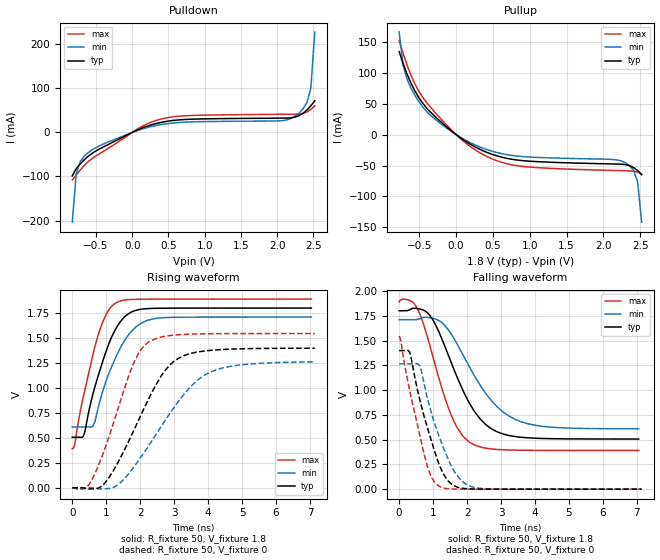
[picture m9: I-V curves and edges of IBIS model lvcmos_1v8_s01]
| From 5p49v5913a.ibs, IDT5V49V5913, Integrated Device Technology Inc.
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[Model]   lvcmos_1v8_s01
Model_type   Output
Polarity   Non-Inverting
|   typ   min   max
C_comp   2pF   1.5pF   2.5pF
Vmeas = 0.9V
Rref = 50
Cref = 0
Vref = 0.9V
|   typ   min   max
[Voltage range]   1.8V   1.71V   1.89V
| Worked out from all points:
|   slope of the pulldown table from 0 to 0.27 V, typ, clamps not added: 15.4 ohm
|   slope of the pullup table from 0 to 0.27 V, typ, clamps not added: 13.1 ohm
|   rising waveform, R_fixture 50, V_fixture 1.8: 20-80 % time 717ps typ, 785ps min, 628ps max; typ from 0.506 V to 1.8 V
|   falling waveform, R_fixture 50, V_fixture 1.8: 20-80 % time 1.03ns typ, 1.23ns min, 819ps max; typ from 1.8 V to 0.506 V
|   rising waveform, R_fixture 50, V_fixture 0: 20-80 % time 1.23ns typ, 1.57ns min, 924ps max; typ from 0 V to 1.4 V
|   falling waveform, R_fixture 50, V_fixture 0: 20-80 % time 678ps typ, 740ps min, 598ps max; typ from 1.4 V to 0 V
[Pulldown]
|Voltage   I (typ)   I (min)   I (max)
|Note, modeling breaks down at 250mA and above.  This is well beyond the functional   |
|operating range of the device.  Should this scenario occur, catastrophic failure and   |
|possible damage to the device and/or board is of higher concern than the I-V curve   |
|behavior.  The IBIS checker will flag currents in excess of 10A with warnings.  Lines   |
|with currents in excess of 0.35 A have been commented out.  The points still remain|
|available to the user if the user desires to use them.   |
|-1.80000e+00   -1.57123e+02   -1.41687e+02   -1.84032e+02
|-1.74600e+00   -1.46350e+02   -1.32525e+02   -1.70600e+02
|-1.69200e+00   -1.35593e+02   -1.23381e+02   -1.57181e+02
|-1.63800e+00   -1.24855e+02   -1.14259e+02   -1.43777e+02
|-1.58400e+00   -1.14140e+02   -1.05164e+02   -1.30391e+02
|-1.53000e+00   -1.03454e+02   -9.61014e+01   -1.17030e+02
|-1.47600e+00   -9.28051e+01   -8.70803e+01   -1.03700e+02
|-1.42200e+00   -8.22059e+01   -7.81126e+01   -9.04125e+01
|-1.36800e+00   -7.16734e+01   -6.92147e+01   -7.71843e+01
|-1.31400e+00   -6.12369e+01   -6.04138e+01   -6.40446e+01
|-1.26000e+00   -5.09378e+01   -5.17410e+01   -5.10499e+01
|-1.20600e+00   -4.08235e+01   -4.32303e+01   -3.82636e+01
|-1.15200e+00   -3.09387e+01   -3.49134e+01   -2.57664e+01
|-1.09800e+00   -2.12858e+01   -2.67907e+01   -1.35591e+01
|-1.04400e+00   -1.18008e+01   -1.88242e+01   -2.48786e+00
|-9.90000e-01   -2.94592e+00   -1.09564e+01   -3.30913e-01
|-9.36000e-01   -5.04093e-01   -3.41190e+00   -1.45436e-01
|-8.82000e-01   -1.55884e-01   -7.28672e-01   -1.19691e-01
-828mV    -98.74mA   -203.8mA   -107.8mA
-774mV    -82.54mA   -94.98mA   -96.94mA
-720mV    -71.89mA   -66.58mA   -85.84mA
-612mV    -54.71mA   -46.44mA   -66.79mA
-450mV    -37.4mA    -30.21mA   -48.14mA
144mV     10.52mA    8.041mA    14.45mA
468mV     24.92mA    19.47mA    32.9mA
2.034V    32.4mA     26.18mA    41.13mA
2.304V    38.17mA    44.17mA    41.74mA
2.412V    50.97mA    67.63mA    46.33mA
2.466V    60.46mA    100.4mA    52.18mA
2.52V     72.02mA    227.8mA    60.53mA
| 2.57400e+00   8.57382e-02   8.78094e-01   7.13755e-02
| 2.62800e+00   1.08415e-01   4.40618e+00   8.43612e-02
| 2.68200e+00   2.11755e-01   1.54961e+01   9.74736e-02
| 2.73600e+00   9.45213e-01   2.77829e+01   1.08890e-01
| 2.79000e+00   6.44762e+00   4.00829e+01   1.24073e-01
| 2.84400e+00   2.08796e+01   5.24028e+01   1.97645e-01
| 2.89800e+00   3.56490e+01   6.47465e+01   1.06236e+00
| 2.95200e+00   5.04441e+01   7.71133e+01   1.09978e+01
| 3.00600e+00   6.52701e+01   8.94994e+01   2.98762e+01
| 3.06000e+00   8.01244e+01   1.01900e+02   4.87902e+01
| 3.11400e+00   9.50001e+01   1.14313e+02   6.77471e+01
| 3.16800e+00   1.09892e+02   1.26734e+02   8.67385e+01
| 3.22200e+00   1.24795e+02   1.39162e+02   1.05753e+02
| 3.27600e+00   1.39706e+02   1.51595e+02   1.24783e+02
| 3.33000e+00   1.54624e+02   1.64032e+02   1.43824e+02
| 3.38400e+00   1.69547e+02   1.76473e+02   1.62872e+02
| 3.43800e+00   1.84473e+02   1.88917e+02   1.81926e+02
| 3.49200e+00   1.99403e+02   2.01364e+02   2.00984e+02
| 3.54600e+00   2.14336e+02   2.13813e+02   2.20045e+02
| 3.60000e+00   2.29271e+02   2.26263e+02   2.39110e+02
[Pullup]
|Voltage   I (typ)   I (min)   I (max)
|Note, modeling breaks down at 250mA and above.  This is well beyond the functional   |
|operating range of the device.  Should this scenario occur, catastrophic failure and   |
|possible damage to the device and/or board is of higher concern than the I-V curve   |
|behavior.  The IBIS checker will flag currents in excess of 10A with warnings.  Lines   |
|with currents in excess of 0.35 A have been commented out.  The points still remain|
|available to the user if the user desires to use them.   |
|-1.80000e+00   2.29375e+02   2.05604e+02   2.71011e+02
|-1.74600e+00   2.14438e+02   1.93155e+02   2.51941e+02
|-1.69200e+00   1.99503e+02   1.80708e+02   2.32873e+02
|-1.63800e+00   1.84571e+02   1.68264e+02   2.13807e+02
|-1.58400e+00   1.69642e+02   1.55823e+02   1.94744e+02
|-1.53000e+00   1.54718e+02   1.43387e+02   1.75685e+02
|-1.47600e+00   1.39798e+02   1.30955e+02   1.56630e+02
|-1.42200e+00   1.24884e+02   1.18529e+02   1.37582e+02
|-1.36800e+00   1.09978e+02   1.06112e+02   1.18541e+02
|-1.31400e+00   9.50841e+01   9.37042e+01   9.95128e+01
|-1.26000e+00   8.02054e+01   8.13103e+01   8.05016e+01
|-1.20600e+00   6.53483e+01   6.89341e+01   6.15174e+01
|-1.15200e+00   5.05195e+01   5.65798e+01   4.25710e+01
|-1.09800e+00   3.57213e+01   4.42495e+01   2.36670e+01
|-1.04400e+00   2.09487e+01   3.19407e+01   5.48601e+00
|-9.90000e-01   6.51330e+00   1.96473e+01   6.02004e-01
|-9.36000e-01   1.00727e+00   7.47441e+00   2.29344e-01
|-8.82000e-01   2.69913e-01   1.53012e+00   1.87713e-01
|-8.28000e-01   1.62186e-01   3.86408e-01   1.69987e-01
-774mV    134.2mA    165.8mA    151.8mA
-720mV    114.6mA    111.9mA    131.2mA
-666mV    97.64mA    89.72mA    112.2mA
-504mV    59.35mA    52.84mA    69.59mA
-342mV    35.66mA    30.61mA    43.41mA
-18mV     1.676mA    1.404mA    2.092mA
360mV     -25.81mA   -21.74mA   -31.86mA
900mV     -42.04mA   -35.5mA    -51.35mA
2.304V    -48.62mA   -45.83mA   -58.53mA
2.412V    -53.4mA    -58.27mA   -59.21mA
2.466V    -58.21mA   -76.35mA   -60.65mA
2.52V     -64.73mA   -141.7mA   -64.05mA
| 2.57400e+00   -7.32856e-02   -4.47707e-01   -6.97922e-02
| 2.62800e+00   -8.79644e-02   -2.00025e+00   -7.77007e-02
| 2.68200e+00   -1.43736e-01   -8.33672e+00   -8.69778e-02
| 2.73600e+00   -4.90693e-01   -1.61824e+01   -9.65121e-02
| 2.79000e+00   -2.93152e+00   -2.41086e+01   -1.08871e-01
| 2.84400e+00   -1.17857e+01   -3.21721e+01   -1.52056e-01
| 2.89800e+00   -2.12700e+01   -4.04227e+01   -5.63058e-01
| 2.95200e+00   -3.09224e+01   -4.88696e+01   -5.50618e+00
| 3.00600e+00   -4.08067e+01   -5.74918e+01   -1.75817e+01
| 3.06000e+00   -5.09214e+01   -6.62527e+01   -2.98766e+01
| 3.11400e+00   -6.12182e+01   -7.51218e+01   -4.24771e+01
| 3.16800e+00   -7.16546e+01   -8.40680e+01   -5.53423e+01
| 3.22200e+00   -8.21870e+01   -9.30724e+01   -6.83916e+01
| 3.27600e+00   -9.27859e+01   -1.02122e+02   -8.15645e+01
| 3.33000e+00   -1.03434e+02   -1.11207e+02   -9.48151e+01
| 3.38400e+00   -1.14120e+02   -1.20320e+02   -1.08118e+02
| 3.43800e+00   -1.24835e+02   -1.29457e+02   -1.21460e+02
| 3.49200e+00   -1.35573e+02   -1.38613e+02   -1.34829e+02
| 3.54600e+00   -1.46330e+02   -1.47785e+02   -1.48221e+02
| 3.60000e+00   -1.57103e+02   -1.56971e+02   -1.61631e+02
[Ramp]
|   typ   min   max
dV/dt_r   0.846/1.241n   0.763/1.578n   0.935/0.933n
dV/dt_f   0.791/1.045n   0.674/1.245n   0.916/0.832n
R_load =   50
[Rising Waveform]
R_fixture = 50
V_fixture = 1.8   |Vcc_typ
V_fixture_min = 1.71 |Vcc_min
V_fixture_max = 1.89 |Vcc_max
C_fixture = 0.0p
| Time   typ   min   max
| 0.00000e+00   5.05771e-01   6.08763e-01   3.90768e-01
| 2.47507e-12   5.05771e-01   6.08763e-01   3.90768e-01
| 4.34525e-12   5.05771e-01   6.08763e-01   3.90768e-01
| 4.57959e-12   5.05771e-01   6.08763e-01   3.90768e-01
| 7.76228e-12   5.05771e-01   6.08763e-01   3.90768e-01
| 1.40250e-11   5.05771e-01   6.08763e-01   3.90768e-01
| 1.46859e-11   5.05771e-01   6.08763e-01   3.90768e-01
| 2.75535e-11   5.05771e-01   6.08763e-01   3.90768e-01
| 3.89156e-11   5.05771e-01   6.08763e-01   3.90768e-01
| 4.27651e-11   5.05771e-01   6.08763e-01   3.90768e-01
| 5.19470e-11   5.05771e-01   6.08763e-01   3.90768e-01
| 6.09735e-11   5.05771e-01   6.08763e-01   3.90768e-01
| 6.28654e-11   5.05771e-01   6.08763e-01   3.90768e-01
| 7.18355e-11   5.05771e-01   6.08763e-01   3.90768e-01
| 7.20853e-11   5.05771e-01   6.08763e-01   3.90768e-01
| 7.57553e-11   5.05771e-01   6.08763e-01   3.90768e-01
| 7.80681e-11   5.05771e-01   6.08763e-01   3.90768e-01
| 7.93944e-11   5.05771e-01   6.08763e-01   3.90768e-01
| 8.55418e-11   5.05771e-01   6.08763e-01   3.90768e-01
| 9.55024e-11   5.05771e-01   6.08763e-01   3.90768e-01
| 9.79222e-11   5.05771e-01   6.08763e-01   3.90768e-01
| 1.07935e-10   5.05771e-01   6.08763e-01   3.90768e-01
| 1.13390e-10   5.05771e-01   6.08763e-01   3.90768e-01
| 1.17787e-10   5.05771e-01   6.08763e-01   3.90768e-01
| 1.27331e-10   5.05771e-01   6.08763e-01   3.90768e-01
| 1.31897e-10   5.05771e-01   6.08763e-01   3.90768e-01
| 1.39387e-10   5.05771e-01   6.08763e-01   3.90768e-01
| 1.47497e-10   5.05771e-01   6.08763e-01   3.90768e-01
| 1.52118e-10   5.05771e-01   6.08763e-01   3.90768e-01
| 1.61717e-10   5.05771e-01   6.08763e-01   3.90768e-01
| 1.72749e-10   5.05771e-01   6.08763e-01   3.90768e-01
| 1.76286e-10   5.05771e-01   6.08763e-01   3.90768e-01
| 1.87607e-10   5.05771e-01   6.08763e-01   3.90768e-01
| 1.97419e-10   5.05771e-01   6.08763e-01   3.90768e-01
| 2.04005e-10   5.05771e-01   6.08763e-01   3.90768e-01
| 2.10686e-10   5.05771e-01   6.08763e-01   3.90768e-01
| 2.18675e-10   5.05771e-01   6.08763e-01   3.90768e-01
| 2.24324e-10   5.05771e-01   6.08763e-01   3.90768e-01
| 2.27448e-10   5.05771e-01   6.08763e-01   3.90768e-01
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0s        505.8mV    608.8mV    390.8mV
71.16ps   505.8mV    608.8mV    434.8mV
183.6ps   505.8mV    608.8mV    674mV
339.8ps   527.7mV    608.8mV    932.5mV
607.1ps   937.5mV    618.3mV    1.332V
930.7ps   1.301V     1.004V     1.687V
1.284ns   1.594V     1.309V     1.852V
1.729ns   1.758V     1.561V     1.886V
2.363ns   1.797V     1.69V      1.889V
7.041ns   1.8V       1.71V      1.89V
[Falling Waveform]
R_fixture = 50
V_fixture = 1.8   |Vcc_typ
V_fixture_min = 1.71 |Vcc_min
V_fixture_max = 1.89 |Vcc_max
C_fixture = 0.0p
| Time   typ   min   max
| 0.00000e+00   1.80000e+00   1.71000e+00   1.89000e+00
| 2.47507e-12   1.80000e+00   1.71000e+00   1.89000e+00
| 4.34525e-12   1.80000e+00   1.71000e+00   1.89000e+00
| 4.57959e-12   1.80000e+00   1.71000e+00   1.89000e+00
| 7.76228e-12   1.80000e+00   1.71000e+00   1.89000e+00
| 1.40250e-11   1.80000e+00   1.71000e+00   1.89000e+00
| 1.46859e-11   1.80000e+00   1.71000e+00   1.89000e+00
| 2.75535e-11   1.80000e+00   1.71000e+00   1.89000e+00
| 3.89154e-11   1.80000e+00   1.71000e+00   1.89000e+00
| 4.27652e-11   1.80000e+00   1.71000e+00   1.89000e+00
| 5.19470e-11   1.80000e+00   1.71000e+00   1.89000e+00
| 6.09735e-11   1.80000e+00   1.71000e+00   1.89000e+00
| 6.28654e-11   1.80000e+00   1.71000e+00   1.89000e+00
| 7.18355e-11   1.80000e+00   1.71000e+00   1.89000e+00
| 7.20853e-11   1.80000e+00   1.71000e+00   1.89000e+00
| 7.57554e-11   1.80000e+00   1.71000e+00   1.89000e+00
| 7.80681e-11   1.80000e+00   1.71000e+00   1.89000e+00
| 7.93945e-11   1.80000e+00   1.71000e+00   1.89000e+00
| 8.55420e-11   1.80000e+00   1.71000e+00   1.89000e+00
| 9.55081e-11   1.80000e+00   1.71000e+00   1.89000e+00
| 9.79276e-11   1.80000e+00   1.71000e+00   1.89000e+00
| 1.07935e-10   1.80000e+00   1.71000e+00   1.89000e+00
| 1.13392e-10   1.80000e+00   1.71000e+00   1.89000e+00
| 1.17787e-10   1.80000e+00   1.71000e+00   1.89000e+00
| 1.27334e-10   1.80000e+00   1.71000e+00   1.89000e+00
| 1.31895e-10   1.80000e+00   1.71000e+00   1.89000e+00
| 1.39384e-10   1.80000e+00   1.71000e+00   1.89000e+00
| 1.47496e-10   1.80000e+00   1.71000e+00   1.89000e+00
| 1.52111e-10   1.80000e+00   1.71000e+00   1.89000e+00
| 1.61709e-10   1.80000e+00   1.71000e+00   1.89000e+00
| 1.73954e-10   1.80000e+00   1.71000e+00   1.89000e+00
| 1.78498e-10   1.80000e+00   1.71000e+00   1.89000e+00
| 1.89981e-10   1.80000e+00   1.71000e+00   1.89000e+00
| 2.00219e-10   1.80000e+00   1.71000e+00   1.89000e+00
| 2.06357e-10   1.80000e+00   1.71000e+00   1.89000e+00
| 2.12276e-10   1.80000e+00   1.71000e+00   1.89000e+00
| 2.22553e-10   1.80000e+00   1.71000e+00   1.89000e+00
| 2.29973e-10   1.80000e+00   1.71000e+00   1.89000e+00
| 2.35974e-10   1.80000e+00   1.71000e+00   1.89000e+00
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0s        1.8V       1.71V      1.89V
478.9ps   1.826V     1.71V      1.856V
681.3ps   1.811V     1.729V     1.702V
926.7ps   1.743V     1.729V     1.42V
1.511ns   1.298V     1.577V     766.1mV
1.71ns    1.128V     1.464V     619.2mV
2.05ns    879.8mV    1.247V     478.9mV
2.717ns   608.7mV    893.8mV    405.6mV
3.58ns    523.9mV    681.9mV    392.7mV
7.054ns   505.8mV    609.1mV    390.8mV
[Rising Waveform]
R_fixture = 50
V_fixture = 0
C_fixture = 0.0p
| Time   typ   min   max
| 0.00000e+00   1.06221e-09   3.51730e-08   4.62084e-10
| 2.47507e-12   1.06262e-09   3.51733e-08   4.62544e-10
| 4.34525e-12   1.06297e-09   3.51737e-08   4.62918e-10
| 4.57959e-12   1.06302e-09   3.51737e-08   4.62965e-10
| 7.76228e-12   1.06362e-09   3.51742e-08   4.63530e-10
| 1.40250e-11   1.06419e-09   3.51751e-08   4.63671e-10
| 1.46859e-11   1.06418e-09   3.51750e-08   4.63682e-10
| 2.75535e-11   1.06272e-09   3.51745e-08   4.61325e-10
| 3.89156e-11   1.06029e-09   3.51724e-08   4.59728e-10
| 4.27651e-11   1.05946e-09   3.51717e-08   4.59288e-10
| 5.19470e-11   1.05748e-09   3.51688e-08   4.58146e-10
| 6.09735e-11   1.05341e-09   3.51645e-08   4.54584e-10
| 6.28654e-11   1.05185e-09   3.51634e-08   4.53687e-10
| 7.18355e-11   1.04369e-09   3.51528e-08   4.47392e-10
| 7.20853e-11   1.04338e-09   3.51523e-08   4.47172e-10
| 7.57553e-11   1.03831e-09   3.51448e-08   4.44030e-10
| 7.80681e-11   1.03592e-09   3.51395e-08   4.44158e-10
| 7.93944e-11   1.03458e-09   3.51384e-08   4.46075e-10
| 8.55418e-11   1.04944e-09   3.51450e-08   4.76465e-10
| 9.55024e-11   1.17116e-09   3.52153e-08   6.31190e-10
| 9.79222e-11   1.20280e-09   3.52569e-08   6.81492e-10
| 1.07935e-10   1.42897e-09   3.54496e-08   8.67329e-10
| 1.13390e-10   1.52704e-09   3.55707e-08   9.22023e-10
| 1.17787e-10   1.59284e-09   3.56684e-08   8.58834e-10
| 1.27331e-10   1.55166e-09   3.57539e-08   6.14819e-10
| 1.31897e-10   1.37650e-09   3.56522e-08   4.33398e-10
| 1.39387e-10   1.01692e-09   3.54726e-08   -2.63290e-11
| 1.47497e-10   3.51343e-10   3.48326e-08   -8.06275e-10
| 1.52118e-10   -3.46989e-10   3.42824e-08   -1.28603e-09
| 1.61717e-10   -1.83017e-09   3.27312e-08   -2.63643e-09
| 1.72749e-10   -3.64856e-09   3.06006e-08   -3.52439e-09
| 1.76286e-10   -3.80599e-09   2.99175e-08   -3.71248e-09
| 1.87607e-10   -3.95808e-09   2.89940e-08   -2.65474e-09
| 1.97419e-10   -2.98220e-09   2.92697e-08   -6.14581e-10
| 2.04005e-10   -1.83318e-09   2.97092e-08   7.75044e-10
| 2.10686e-10   -5.93254e-10   3.06172e-08   2.61539e-09
| 2.18675e-10   1.17879e-09   3.17029e-08   4.90271e-09
| 2.24324e-10   2.56429e-09   3.26181e-08   6.38370e-09
| 2.27448e-10   3.44845e-09   3.31385e-08   7.01029e-09
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0s        1.062nV    35.17nV    462.1pV
459.4ps   -12.33mV   99.49uV    18.25mV
967.7ps   50.87mV    -10.31mV   397.6mV
1.699ns   492.3mV    156.9mV    1.157V
1.999ns   710.4mV    296.3mV    1.373V
2.26ns    897.1mV    427.3mV    1.462V
2.993ns   1.267V     802.2mV    1.529V
3.566ns   1.351V     1.04V      1.539V
4.078ns   1.376V     1.16V      1.543V
7.141ns   1.398V     1.261V     1.545V
[Falling Waveform]
R_fixture = 50
V_fixture = 0
C_fixture = 0.0p
| Time   typ   min   max
| 0.00000e+00   1.39821e+00   1.26477e+00   1.54491e+00
| 1.13297e-09   1.39821e+00   1.26477e+00   1.54489e+00
| 1.15654e-09   1.39821e+00   1.26477e+00   1.54487e+00
| 1.20310e-09   1.39821e+00   1.26477e+00   1.54480e+00
| 1.22516e-09   1.39821e+00   1.26477e+00   1.54480e+00
| 1.25132e-09   1.39821e+00   1.26477e+00   1.54496e+00
| 1.26439e-09   1.39821e+00   1.26477e+00   1.54510e+00
| 1.27876e-09   1.39821e+00   1.26477e+00   1.54536e+00
| 1.29689e-09   1.39821e+00   1.26477e+00   1.54628e+00
| 1.30629e-09   1.39821e+00   1.26477e+00   1.54688e+00
| 1.31897e-09   1.39820e+00   1.26477e+00   1.54745e+00
| 1.33029e-09   1.39820e+00   1.26477e+00   1.54738e+00
| 1.34255e-09   1.39820e+00   1.26477e+00   1.54629e+00
| 1.36105e-09   1.39819e+00   1.26477e+00   1.54125e+00
| 1.37123e-09   1.39818e+00   1.26477e+00   1.53608e+00
| 1.38167e-09   1.39817e+00   1.26477e+00   1.52844e+00
| 1.39232e-09   1.39816e+00   1.26477e+00   1.51725e+00
| 1.40750e-09   1.39815e+00   1.26477e+00   1.49514e+00
| 1.42228e-09   1.39813e+00   1.26477e+00   1.46578e+00
| 1.42934e-09   1.39812e+00   1.26477e+00   1.45058e+00
| 1.45187e-09   1.39810e+00   1.26477e+00   1.40164e+00
| 1.46411e-09   1.39810e+00   1.26477e+00   1.37458e+00
| 1.47719e-09   1.39811e+00   1.26477e+00   1.34584e+00
| 1.49094e-09   1.39818e+00   1.26477e+00   1.31637e+00
| 1.50104e-09   1.39824e+00   1.26477e+00   1.29544e+00
| 1.51336e-09   1.39835e+00   1.26477e+00   1.27082e+00
| 1.52594e-09   1.39854e+00   1.26477e+00   1.24614e+00
| 1.54323e-09   1.39893e+00   1.26476e+00   1.21324e+00
| 1.55765e-09   1.39944e+00   1.26476e+00   1.18657e+00
| 1.56186e-09   1.39962e+00   1.26476e+00   1.17896e+00
| 1.57669e-09   1.40025e+00   1.26475e+00   1.15210e+00
| 1.59728e-09   1.40058e+00   1.26474e+00   1.11575e+00
| 1.59998e-09   1.40048e+00   1.26474e+00   1.11110e+00
| 1.61755e-09   1.39921e+00   1.26473e+00   1.08085e+00
| 1.62715e-09   1.39761e+00   1.26472e+00   1.06466e+00
| 1.63923e-09   1.39441e+00   1.26471e+00   1.04441e+00
| 1.65111e-09   1.38966e+00   1.26470e+00   1.02482e+00
| 1.67565e-09   1.37309e+00   1.26467e+00   9.84947e-01
| 1.67799e-09   1.37065e+00   1.26467e+00   9.81250e-01
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0s        1.398V     1.265V     1.545V
316.5ps   1.373V     1.265V     984.9mV
602.3ps   909.4mV    1.244V     552.9mV
843.5ps   607.6mV    904.8mV    215.7mV
945ps     492.6mV    775.4mV    125.1mV
1.198ns   233.5mV    513.7mV    24.38mV
1.428ns   87.66mV    315.7mV    5.158mV
1.719ns   18.84mV    132.2mV    736.1uV
2.245ns   1.153mV    15.2mV     106.8uV
7.141ns   -520.4nV   -467.1nV   -404.3nV
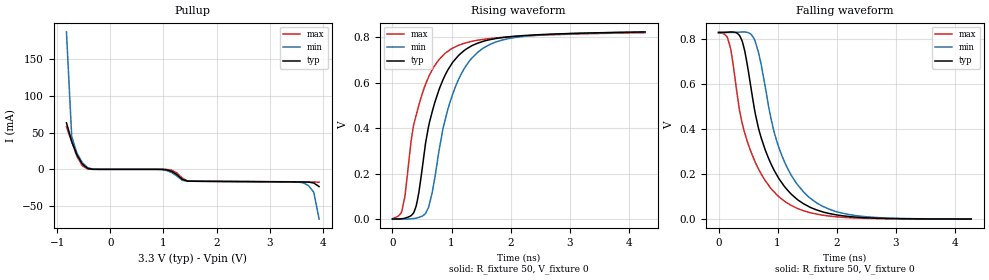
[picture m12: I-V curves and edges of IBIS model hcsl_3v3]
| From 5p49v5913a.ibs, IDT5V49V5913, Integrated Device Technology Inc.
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|   Model HCSL_3V3
[Model]   hcsl_3v3
Model_type   Open_source
Polarity   Non-Inverting
|   typ   min   max
C_comp   2pF   1.5pF   2.5pF
Vmeas = 0.444V
Rref = 50
Cref = 0
Vref = 0V
|   typ   min   max
[Voltage range]   3.3V   3.135V   3.465V
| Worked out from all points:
|   rising waveform, R_fixture 50, V_fixture 0: 20-80 % time 471ps typ, 502ps min, 433ps max; typ from 0 V to 0.824 V
|   falling waveform, R_fixture 50, V_fixture 0: 20-80 % time 558ps typ, 563ps min, 544ps max; typ from 0.831 V to 0 V
[Pullup]
|Voltage   I (typ)   I (min)   I (max)
|Note, modeling breaks down at 250mA and above.  This is well beyond the functional   |
|operating range of the device.  Should this scenario occur, catastrophic failure and   |
|possible damage to the device and/or board is of higher concern than the I-V curve   |
|behavior.  The IBIS checker will flag currents in excess of 10A with warnings.  Lines   |
|with currents in excess of 0.35 A have been commented out.  The points still remain|
|available to the user if the user desires to use them.   |
|-3.30000e+00   6.40327e+02   5.47500e+02   7.96702e+02
|-3.20100e+00   6.12909e+02   5.24641e+02   7.61711e+02
|-3.10200e+00   5.85494e+02   5.01783e+02   7.26721e+02
|-3.00300e+00   5.58079e+02   4.78928e+02   6.91732e+02
|-2.90400e+00   5.30667e+02   4.56074e+02   6.56745e+02
|-2.80500e+00   5.03256e+02   4.33222e+02   6.21760e+02
|-2.70600e+00   4.75847e+02   4.10372e+02   5.86777e+02
|-2.60700e+00   4.48440e+02   3.87524e+02   5.51795e+02
|-2.50800e+00   4.21035e+02   3.64678e+02   5.16815e+02
|-2.40900e+00   3.93632e+02   3.41834e+02   4.81838e+02
|-2.31000e+00   3.66231e+02   3.18993e+02   4.46862e+02
|-2.21100e+00   3.38833e+02   2.96154e+02   4.11889e+02
|-2.11200e+00   3.11439e+02   2.73319e+02   3.76919e+02
|-2.01300e+00   2.84047e+02   2.50488e+02   3.41952e+02
|-1.91400e+00   2.56660e+02   2.27660e+02   3.06989e+02
|-1.81500e+00   2.29278e+02   2.04838e+02   2.72031e+02
|-1.71600e+00   2.01902e+02   1.82023e+02   2.37078e+02
|-1.61700e+00   1.74535e+02   1.59216e+02   2.02133e+02
|-1.51800e+00   1.47179e+02   1.36422e+02   1.67199e+02
|-1.41900e+00   1.19841e+02   1.13645e+02   1.32281e+02
|-1.32000e+00   9.25327e+01   9.08955e+01   9.73937e+01
|-1.22100e+00   6.52757e+01   6.81910e+01   6.25644e+01
|-1.12200e+00   3.81062e+01   4.55556e+01   2.78509e+01
|-1.02300e+00   1.10290e+01   2.29953e+01   1.17586e+00
|-9.24000e-01   3.71943e-01   3.02871e+00   8.33409e-02
-825mV    63.35mA    186.9mA    57.84mA
-726mV    37.97mA    44.71mA    37.31mA
-627mV    19.63mA    21.88mA    17.56mA
-528mV    7.306mA    9.415mA    5.083mA
-429mV    1.322mA    2.467mA    481.2uA
1.056V    -527.3uA   -1.465mA   -35.97uA
1.254V    -7.244mA   -9.093mA   -4.964mA
1.452V    -15.98mA   -16.05mA   -15.83mA
3.63V     -17.16mA   -18.29mA   -17.03mA
3.729V    -17.34mA   -22.18mA   -17.12mA
3.828V    -18.52mA   -31.24mA   -17.23mA
3.927V    -23.42mA   -67.52mA   -17.42mA
| 4.02600e+00   -3.32694e-02   -5.43392e-01   -1.86972e-02
| 4.12500e+00   -5.01334e-02   -8.21896e+00   -2.51934e-02
| 4.22400e+00   -2.09443e-01   -2.25334e+01   -3.82149e-02
| 4.32300e+00   -5.39256e+00   -3.69151e+01   -5.37428e-02
| 4.42200e+00   -2.25883e+01   -5.13711e+01   -9.27713e-02
| 4.52100e+00   -3.98763e+01   -6.58862e+01   -2.41409e+00
| 4.62000e+00   -5.72515e+01   -8.04394e+01   -2.34185e+01
| 4.71900e+00   -7.46917e+01   -9.50119e+01   -4.55417e+01
| 4.81800e+00   -9.21611e+01   -1.09596e+02   -6.77677e+01
| 4.91700e+00   -1.09646e+02   -1.24189e+02   -9.00511e+01
| 5.01600e+00   -1.27141e+02   -1.38787e+02   -1.12355e+02
| 5.11500e+00   -1.44643e+02   -1.53390e+02   -1.34671e+02
| 5.21400e+00   -1.62149e+02   -1.67995e+02   -1.56993e+02
| 5.31300e+00   -1.79658e+02   -1.82604e+02   -1.79320e+02
| 5.41200e+00   -1.97169e+02   -1.97214e+02   -2.01649e+02
| 5.51100e+00   -2.14683e+02   -2.11826e+02   -2.23981e+02
| 5.61000e+00   -2.32197e+02   -2.26439e+02   -2.46314e+02
| 5.70900e+00   -2.49713e+02   -2.41053e+02   -2.68647e+02
| 5.80800e+00   -2.67230e+02   -2.55668e+02   -2.90982e+02
| 5.90700e+00   -2.84747e+02   -2.70284e+02   -3.13316e+02
| 6.00600e+00   -3.02264e+02   -2.84901e+02   -3.35651e+02
| 6.10500e+00   -3.19782e+02   -2.99517e+02   -3.57986e+02
| 6.20400e+00   -3.37301e+02   -3.14135e+02   -3.80321e+02
| 6.30300e+00   -3.54819e+02   -3.28752e+02   -4.02656e+02
| 6.40200e+00   -3.72338e+02   -3.43370e+02   -4.24991e+02
| 6.50100e+00   -3.89857e+02   -3.57989e+02   -4.47326e+02
| 6.60000e+00   -4.07376e+02   -3.72607e+02   -4.69660e+02
[Ramp]
|   typ   min   max
dV/dt_r   0.494/0.47n  0.494/0.501n   0.492/0.433n
dV/dt_f   0.499/0.558n   0.499/0.563n   0.497/0.544n
[Rising Waveform]
R_fixture = 50
V_fixture = 0
C_fixture = 0.0p
| Time   typ   min   max
| 0.00000e+00   1.36186e-07   2.87324e-07   2.02623e-07
| 2.69541e-12   1.38830e-07   2.89848e-07   2.05383e-07
| 4.88539e-12   1.40146e-07   2.91129e-07   2.06732e-07
| 5.15560e-12   1.40267e-07   2.91209e-07   2.06895e-07
| 8.43815e-12   1.41229e-07   2.92090e-07   2.07861e-07
| 1.48886e-11   1.39704e-07   2.91572e-07   2.05992e-07
| 1.56443e-11   1.39741e-07   2.92080e-07   2.05758e-07
| 2.89352e-11   1.44294e-07   3.03526e-07   2.05222e-07
| 4.35601e-11   1.98901e-07   3.64939e-07   2.65854e-07
| 4.98146e-11   2.41560e-07   3.99053e-07   2.93088e-07
| 5.87317e-11   3.02378e-07   4.55497e-07   3.56106e-07
| 7.00000e-11   3.47837e-07   4.75319e-07   4.26344e-07
| 7.43358e-11   2.91776e-07   3.93213e-07   4.09021e-07
| 7.98945e-11   1.69360e-07   2.35651e-07   3.59553e-07
| 8.04793e-11   1.56409e-07   2.15853e-07   3.53653e-07
| 8.54764e-11   7.89193e-09   2.99141e-08   3.10002e-07
| 9.54720e-11   -6.98030e-08   -1.47653e-07   3.82797e-07
| 9.66854e-11   -7.81103e-08   -1.43120e-07   4.27923e-07
| 1.09530e-10   4.59644e-07   3.15651e-07   9.20927e-07
| 1.16741e-10   9.75044e-07   8.77482e-07   1.24245e-06
| 1.21843e-10   1.29042e-06   1.30251e-06   1.29783e-06
| 1.33386e-10   1.79399e-06   2.04497e-06   1.30436e-06
| 1.41861e-10   1.53109e-06   1.97175e-06   9.47651e-07
| 1.49567e-10   7.60508e-07   1.75617e-06   -2.89512e-07
| 1.59253e-10   -1.07070e-06   -3.35512e-07   -3.18476e-06
| 1.72966e-10   -7.53683e-06   -5.97567e-06   -9.48905e-06
| 1.80038e-10   -1.16017e-05   -9.43776e-06   -1.45940e-05
| 1.97875e-10   -2.37334e-05   -2.13625e-05   -2.76201e-05
| 2.11185e-10   -3.27803e-05   -3.00115e-05   -3.75776e-05
| 2.26992e-10   -4.28784e-05   -4.00509e-05   -4.72207e-05
| 2.42659e-10   -5.22517e-05   -4.84231e-05   -5.31446e-05
| 2.50985e-10   -5.44654e-05   -5.28724e-05   -5.16594e-05
| 2.61567e-10   -5.36465e-05   -5.56664e-05   -4.50052e-05
| 2.71214e-10   -5.02836e-05   -5.48402e-05   -3.77600e-05
| 2.81034e-10   -4.43584e-05   -5.25341e-05   -3.23665e-05
| 2.85074e-10   -4.21421e-05   -5.05811e-05   -3.02571e-05
| 2.96364e-10   -3.64990e-05   -4.52158e-05   -2.58007e-05
| 3.10065e-10   -3.09558e-05   -3.90862e-05   -2.16442e-05
| 3.11343e-10   -3.05063e-05   -3.86013e-05   -2.12564e-05
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0s        136.2nV    287.3nV    202.6nV
156.8ps   1.071mV    -79.32uV   33.71mV
212.3ps   3.774mV    -136.6uV   103.2mV
373.4ps   36.28mV    2.333mV    428.6mV
446.5ps   115.8mV    7.104mV    501mV
607.8ps   402.7mV    48.22mV    622.8mV
890.9ps   632.9mV    435.1mV    729.7mV
1.232ns   745.4mV    669.5mV    775.1mV
1.661ns   790.4mV    769.9mV    794.9mV
4.28ns    823.8mV    823.2mV    820.5mV
[Falling Waveform]
R_fixture = 50
V_fixture = 0
C_fixture = 0.0p
| Time   typ   min   max
| 0.00000e+00   8.31427e-01   8.31146e-01   8.27672e-01
| 7.98945e-11   8.31427e-01   8.31146e-01   8.27673e-01
| 8.58813e-11   8.31426e-01   8.31144e-01   8.27671e-01
| 9.61976e-11   8.31422e-01   8.31141e-01   8.27667e-01
| 1.07460e-10   8.31417e-01   8.31136e-01   8.27662e-01
| 1.16741e-10   8.31414e-01   8.31133e-01   8.27658e-01
| 1.21843e-10   8.31412e-01   8.31132e-01   8.27656e-01
| 1.33386e-10   8.31409e-01   8.31129e-01   8.27652e-01
| 1.46204e-10   8.31405e-01   8.31126e-01   8.27647e-01
| 1.54774e-10   8.31401e-01   8.31122e-01   8.27643e-01
| 1.63175e-10   8.31396e-01   8.31118e-01   8.27636e-01
| 1.76539e-10   8.31386e-01   8.31108e-01   8.27625e-01
| 1.92143e-10   8.31370e-01   8.31093e-01   8.27609e-01
| 2.03739e-10   8.31360e-01   8.31082e-01   8.27598e-01
| 2.19053e-10   8.31346e-01   8.31070e-01   8.27588e-01
| 2.35722e-10   8.31338e-01   8.31059e-01   8.27580e-01
| 2.47904e-10   8.31334e-01   8.31053e-01   8.27585e-01
| 2.55656e-10   8.31334e-01   8.31051e-01   8.27594e-01
| 2.64452e-10   8.31341e-01   8.31051e-01   8.27606e-01
| 2.72380e-10   8.31348e-01   8.31056e-01   8.27617e-01
| 2.82934e-10   8.31361e-01   8.31063e-01   8.27631e-01
| 2.93815e-10   8.31374e-01   8.31074e-01   8.27644e-01
| 2.97820e-10   8.31378e-01   8.31079e-01   8.27649e-01
| 3.10528e-10   8.31393e-01   8.31092e-01   8.27662e-01
| 3.24274e-10   8.31407e-01   8.31107e-01   8.27673e-01
| 3.27756e-10   8.31411e-01   8.31111e-01   8.27676e-01
| 3.44211e-10   8.31426e-01   8.31127e-01   8.27686e-01
| 3.61215e-10   8.31437e-01   8.31143e-01   8.27692e-01
| 3.71863e-10   8.31443e-01   8.31150e-01   8.27696e-01
| 3.90984e-10   8.31452e-01   8.31163e-01   8.27699e-01
| 4.10651e-10   8.31457e-01   8.31173e-01   8.27702e-01
| 4.23537e-10   8.31461e-01   8.31177e-01   8.27704e-01
| 4.43238e-10   8.31464e-01   8.31184e-01   8.27707e-01
| 4.64799e-10   8.31468e-01   8.31189e-01   8.27711e-01
| 4.84315e-10   8.31472e-01   8.31193e-01   8.27714e-01
| 5.01609e-10   8.31475e-01   8.31197e-01   8.27715e-01
| 5.20197e-10   8.31478e-01   8.31201e-01   8.27715e-01
| 5.25772e-10   8.31478e-01   8.31202e-01   8.27714e-01
| 5.45758e-10   8.31479e-01   8.31204e-01   8.27710e-01
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0s        831.4mV    831.1mV    827.7mV
204.1ps   833.4mV    831mV      759.8mV
373.4ps   809.4mV    832.8mV    462.1mV
607.8ps   491.3mV    801.4mV    262.4mV
797.1ps   304mV      580.7mV    169mV
939.8ps   218.4mV    390.2mV    121.6mV
1.118ns   144.8mV    254.5mV    79.46mV
1.441ns   68.29mV    120.7mV    37.07mV
1.976ns   19.61mV    34.66mV    10.62mV
4.28ns    197.7uV    266.8uV    157uV
